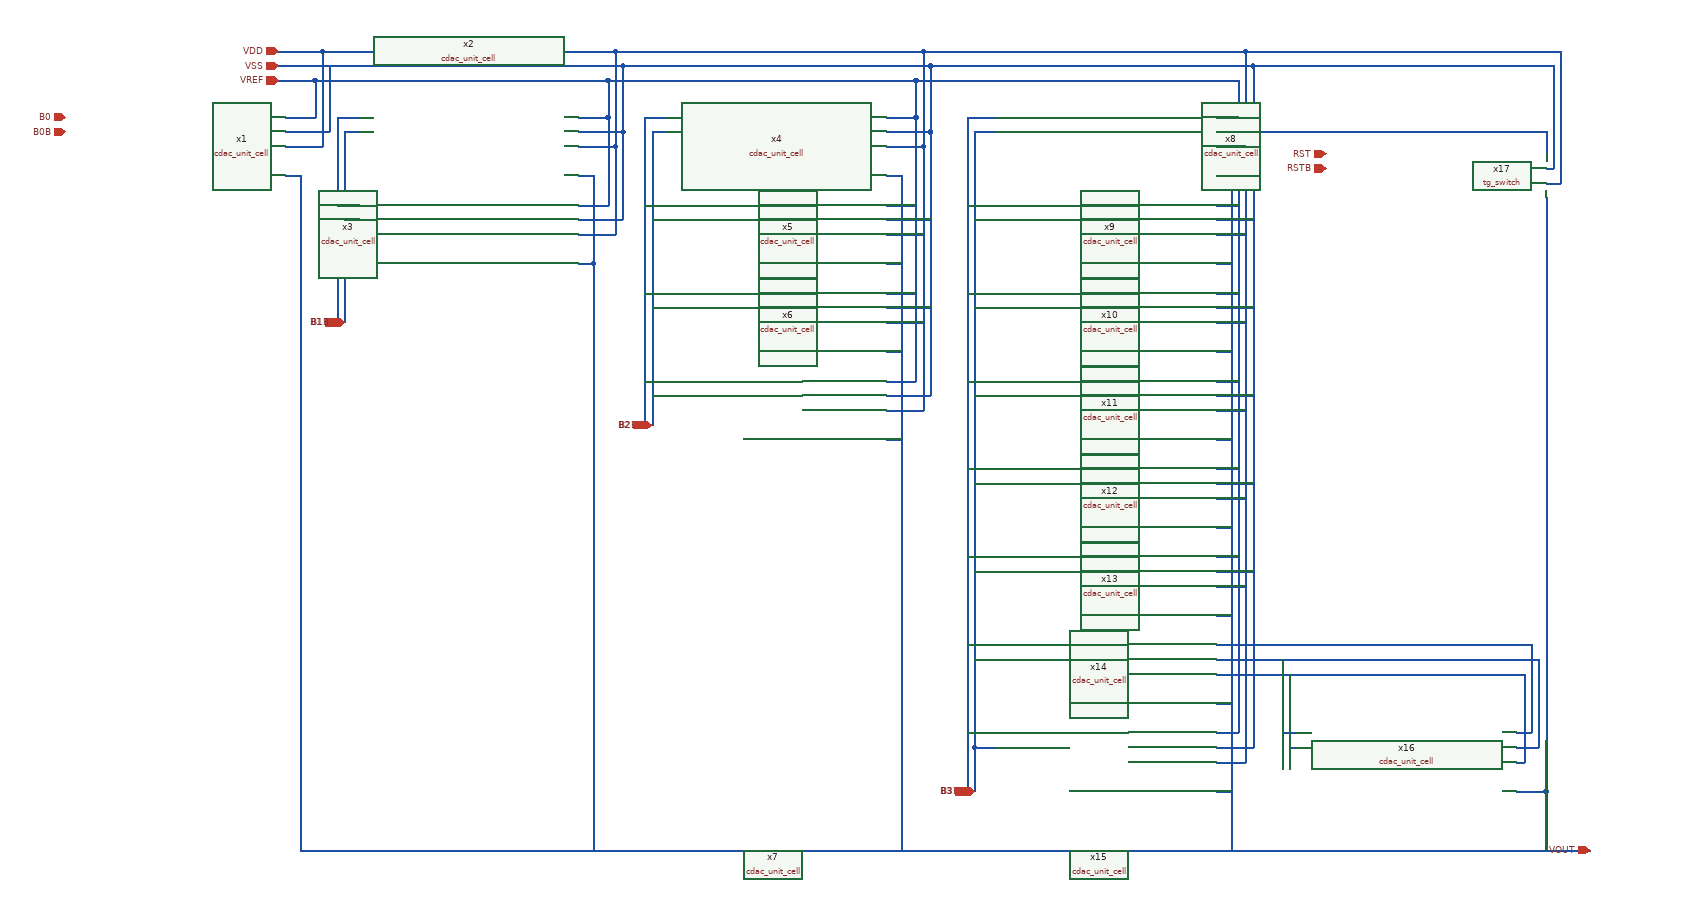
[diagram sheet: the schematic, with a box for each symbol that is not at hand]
v {xschem version=3.4.7 file_version=1.2}
G {}
K {}
V {}
S {}
E {}
N -50 40 -30 40 {lab=VOUT}
N -30 40 -30 450 {lab=VOUT}
N -30 960 810 960 {lab=VOUT}
N 350 160 370 160 {lab=VOUT}
N 370 160 370 450 {lab=VOUT}
N 370 40 370 160 {lab=VOUT}
N 350 40 370 40 {lab=VOUT}
N 770 40 790 40 {lab=VOUT}
N 790 40 790 450 {lab=VOUT}
N 770 160 790 160 {lab=VOUT}
N 770 280 790 280 {lab=VOUT}
N 770 400 790 400 {lab=VOUT}
N -50 -40 -30 -40 {lab=VREF}
N 390 -90 390 -40 {lab=VREF}
N 350 -40 390 -40 {lab=VREF}
N 390 -40 390 80 {lab=VREF}
N 350 80 390 80 {lab=VREF}
N -30 -40 -10 -40 {lab=VREF}
N -10 -90 -10 -40 {lab=VREF}
N -10 -90 390 -90 {lab=VREF}
N 390 -90 810 -90 {lab=VREF}
N 810 -90 810 -40 {lab=VREF}
N 770 -40 810 -40 {lab=VREF}
N 810 -40 810 320 {lab=VREF}
N 770 320 810 320 {lab=VREF}
N 770 200 810 200 {lab=VREF}
N 770 80 810 80 {lab=VREF}
N -60 -90 -10 -90 {lab=VREF}
N -60 -110 410 -110 {lab=VSS}
N 410 -110 410 -20 {lab=VSS}
N 350 -20 410 -20 {lab=VSS}
N -50 -20 10 -20 {lab=VSS}
N 10 -110 10 -20 {lab=VSS}
N 410 -20 410 100 {lab=VSS}
N 350 100 410 100 {lab=VSS}
N 770 -20 830 -20 {lab=VSS}
N 830 -20 830 340 {lab=VSS}
N 770 340 830 340 {lab=VSS}
N 770 220 830 220 {lab=VSS}
N 770 100 830 100 {lab=VSS}
N -50 0 -0 -0 {lab=VDD}
N -0 -130 -0 0 {lab=VDD}
N -60 -130 -0 -130 {lab=VDD}
N -0 -130 400 -130 {lab=VDD}
N 400 -130 400 -0 {lab=VDD}
N 350 0 400 0 {lab=VDD}
N 400 -0 400 120 {lab=VDD}
N 350 120 400 120 {lab=VDD}
N 400 -130 820 -130 {lab=VDD}
N 770 0 820 0 {lab=VDD}
N 820 -0 820 360 {lab=VDD}
N 770 360 820 360 {lab=VDD}
N 770 240 820 240 {lab=VDD}
N 770 120 820 120 {lab=VDD}
N 30 -20 50 -20 {lab=B1B}
N 30 -20 30 240 {lab=B1B}
N 30 100 50 100 {lab=B1B}
N 20 -40 50 -40 {lab=B1}
N 20 -40 20 240 {lab=B1}
N 20 80 50 80 {lab=B1}
N 450 -20 470 -20 {lab=B2B}
N 450 -20 450 380 {lab=B2B}
N 450 100 470 100 {lab=B2B}
N 450 220 470 220 {lab=B2B}
N 450 340 470 340 {lab=B2B}
N 440 -40 470 -40 {lab=B2}
N 440 -40 440 380 {lab=B2}
N 440 320 470 320 {lab=B2}
N 440 200 470 200 {lab=B2}
N 440 80 470 80 {lab=B2}
N 820 -130 820 -0 {lab=VDD}
N 830 -110 830 -20 {lab=VSS}
N 800 -110 830 -110 {lab=VSS}
N 410 -110 800 -110 {lab=VSS}
N -30 450 -30 960 {lab=VOUT}
N 790 450 790 960 {lab=VOUT}
N 370 450 370 950 {lab=VOUT}
N 370 950 370 960 {lab=VOUT}
N 810 960 1330 960 {lab=VOUT}
N 810 -90 1250 -90 {lab=VREF}
N 1250 -90 1250 800 {lab=VREF}
N 1220 800 1250 800 {lab=VREF}
N 1220 560 1250 560 {lab=VREF}
N 1220 440 1250 440 {lab=VREF}
N 1220 320 1250 320 {lab=VREF}
N 1220 200 1250 200 {lab=VREF}
N 1220 80 1250 80 {lab=VREF}
N 1220 -40 1250 -40 {lab=VREF}
N 820 -130 1260 -130 {lab=VDD}
N 1260 -130 1260 840 {lab=VDD}
N 1220 840 1260 840 {lab=VDD}
N 1220 720 1260 720 {lab=VDD}
N 1220 600 1260 600 {lab=VDD}
N 1220 480 1260 480 {lab=VDD}
N 1220 360 1260 360 {lab=VDD}
N 1220 240 1260 240 {lab=VDD}
N 1220 120 1260 120 {lab=VDD}
N 1220 -0 1260 -0 {lab=VDD}
N 830 -110 1270 -110 {lab=VSS}
N 1270 -110 1270 820 {lab=VSS}
N 1220 820 1270 820 {lab=VSS}
N 1220 700 1270 700 {lab=VSS}
N 1220 580 1270 580 {lab=VSS}
N 1220 460 1270 460 {lab=VSS}
N 1220 340 1270 340 {lab=VSS}
N 1220 220 1270 220 {lab=VSS}
N 1220 100 1270 100 {lab=VSS}
N 1220 -20 1270 -20 {lab=VSS}
N 1220 40 1240 40 {lab=VOUT}
N 1240 40 1240 960 {lab=VOUT}
N 1220 880 1240 880 {lab=VOUT}
N 1220 760 1240 760 {lab=VOUT}
N 1220 640 1240 640 {lab=VOUT}
N 1220 520 1240 520 {lab=VOUT}
N 1220 400 1240 400 {lab=VOUT}
N 1220 280 1240 280 {lab=VOUT}
N 1220 160 1240 160 {lab=VOUT}
N 890 820 890 880 {lab=B3B}
N 890 820 920 820 {lab=B3B}
N 890 -20 890 820 {lab=B3B}
N 890 -20 920 -20 {lab=B3B}
N 890 100 920 100 {lab=B3B}
N 890 220 920 220 {lab=B3B}
N 890 340 920 340 {lab=B3B}
N 890 460 920 460 {lab=B3B}
N 890 580 920 580 {lab=B3B}
N 890 700 920 700 {lab=B3B}
N 880 -40 880 880 {lab=B3}
N 880 -40 910 -40 {lab=B3}
N 910 -40 920 -40 {lab=B3}
N 880 80 920 80 {lab=B3}
N 880 200 920 200 {lab=B3}
N 880 320 920 320 {lab=B3}
N 880 440 920 440 {lab=B3}
N 880 560 920 560 {lab=B3}
N 880 680 920 680 {lab=B3}
N 880 800 920 800 {lab=B3}
N 1670 880 1670 930 {lab=VOUT}
N 1630 880 1670 880 {lab=VOUT}
N 1640 720 1640 840 {lab=VDD}
N 1270 700 1660 700 {lab=VSS}
N 1660 700 1660 820 {lab=VSS}
N 1630 800 1650 800 {lab=VREF}
N 1650 680 1650 800 {lab=VREF}
N 1220 680 1250 680 {lab=VREF}
N 1250 680 1650 680 {lab=VREF}
N 1330 960 1730 960 {lab=VOUT}
N 1670 930 1670 960 {lab=VOUT}
N 1310 800 1330 800 {lab=VSS}
N 1320 820 1330 820 {lab=VDD}
N 1320 720 1320 820 {lab=VDD}
N 1310 700 1310 800 {lab=VSS}
N 1270 -20 1650 -20 {lab=VSS}
N 1630 840 1640 840 {lab=VDD}
N 1260 720 1640 720 {lab=VDD}
N 1630 820 1660 820 {lab=VSS}
N 1670 190 1670 880 {lab=VOUT}
N 1670 70 1670 190 {lab=VOUT}
N 1670 -20 1670 10 {lab=VSS}
N 1650 -20 1670 -20 {lab=VSS}
N 1270 -110 1680 -110 {lab=VSS}
N 1680 -110 1680 30 {lab=VSS}
N 1670 30 1680 30 {lab=VSS}
N 1670 50 1690 50 {lab=VDD}
N 1690 -130 1690 50 {lab=VDD}
N 1260 -130 1690 -130 {lab=VDD}
C {libs/core_matchmaker/cdac_unit/cdac_unit_cell.sym} -200 0 0 0 {name=x1}
C {libs/core_matchmaker/cdac_unit/cdac_unit_cell.sym} 200 0 0 0 {name=x2}
C {libs/core_matchmaker/cdac_unit/cdac_unit_cell.sym} 200 120 0 0 {name=x3}
C {libs/core_matchmaker/cdac_unit/cdac_unit_cell.sym} 620 0 0 0 {name=x4}
C {libs/core_matchmaker/cdac_unit/cdac_unit_cell.sym} 620 120 0 0 {name=x5}
C {libs/core_matchmaker/cdac_unit/cdac_unit_cell.sym} 620 240 0 0 {name=x6}
C {libs/core_matchmaker/cdac_unit/cdac_unit_cell.sym} 620 360 0 0 {name=x7}
C {iopin.sym} 1730 960 0 0 {name=VOUT lab=VOUT}
C {ipin.sym} -60 -90 0 0 {name=VREF lab=VREF}
C {ipin.sym} -60 -110 0 0 {name=VSS lab=VSS}
C {ipin.sym} -60 -130 0 0 {name=VDD lab=VDD}
C {ipin.sym} -350 -20 0 0 {name=B0B lab=B0B}
C {ipin.sym} -350 -40 0 0 {name=B0 lab=B0}
C {ipin.sym} 20 240 3 0 {name=B1 lab=B1}
C {ipin.sym} 30 240 2 0 {name=B1B lab=B1B}
C {ipin.sym} 450 380 3 0 {name=B2B lab=B2B}
C {ipin.sym} 440 380 0 0 {name=B3 lab=B2}
C {libs/core_matchmaker/cdac_unit/cdac_unit_cell.sym} 1070 0 0 0 {name=x8}
C {libs/core_matchmaker/cdac_unit/cdac_unit_cell.sym} 1070 120 0 0 {name=x9}
C {libs/core_matchmaker/cdac_unit/cdac_unit_cell.sym} 1070 240 0 0 {name=x10}
C {libs/core_matchmaker/cdac_unit/cdac_unit_cell.sym} 1070 360 0 0 {name=x11}
C {libs/core_matchmaker/cdac_unit/cdac_unit_cell.sym} 1070 480 0 0 {name=x12}
C {libs/core_matchmaker/cdac_unit/cdac_unit_cell.sym} 1070 600 0 0 {name=x13}
C {libs/core_matchmaker/cdac_unit/cdac_unit_cell.sym} 1070 720 0 0 {name=x14}
C {libs/core_matchmaker/cdac_unit/cdac_unit_cell.sym} 1070 840 0 0 {name=x15}
C {ipin.sym} 890 880 3 0 {name=B2 lab=B3B}
C {ipin.sym} 880 880 0 0 {name=B4 lab=B3}
C {libs/core_matchmaker/cdac_unit/cdac_unit_cell.sym} 1480 840 0 0 {name=x16}
C {libs/core_matchmaker/tg_switch/tg_switch.sym} 1520 40 0 0 {name=x17}
C {ipin.sym} 1370 10 0 0 {name=RST lab=RST}
C {ipin.sym} 1370 30 0 0 {name=RSTB lab=RSTB}
